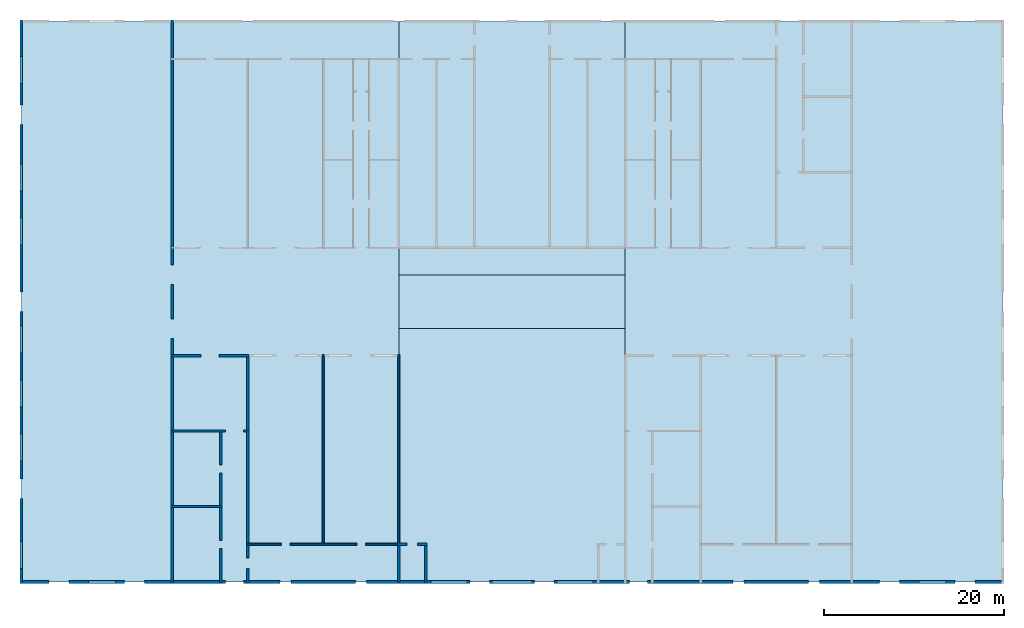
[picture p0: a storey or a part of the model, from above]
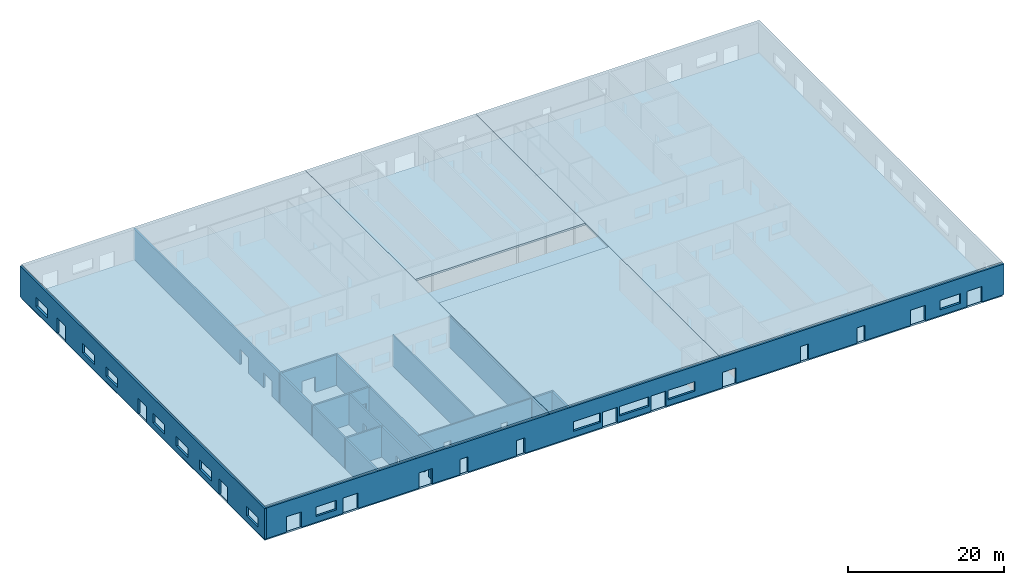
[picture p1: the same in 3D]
Properties of the parts of a building model (IFC4)

# File
Description: ViewDefinition[DesignTransferView]
File name: /dev/null
Time: 2026-10-29T19:15:48+03:00
Written by: IfcOpenShell 0.9.0.post1
Made in: IfcOpenShell 0.9.0.post1
Authorization: Nobody

# IfcBuildingStorey, Ground Floor
In: Sample Shopping Mall
Elevation: 0 mm

# IfcSpace (45)
In: Ground Floor
Name | Description | LongName = Reference
01 | الممشى الرئيسي والأتريوم | MALL STREET & ATRIUM
02 | مصاعد | LIFTS
03 | مصاعد | LIFTS
04 | المتجر الرئيسي | ANCHOR STORE W
05 | المتجر الرئيسي | ANCHOR STORE E
06 | ممر الخدمة | SERVICE CORRIDOR SW1
07 | ممر الخدمة | SERVICE CORRIDOR SE2
08 | ممر الخدمة | SERVICE CORRIDOR NW1
09 | ممر الخدمة | SERVICE CORRIDOR NE2
10 | درج الهروب | ESCAPE STAIR 1
11 | ممر الهروب | PASSAGE 1
12 | مجرى كهرباء | ELEC RISER 1
13 | مجرى ميكانيكا | MECH RISER 1
14 | محل تجاري | SHOP 01
15 | محل تجاري | SHOP 02
16 | درج الهروب | ESCAPE STAIR 2
17 | ممر الهروب | PASSAGE 2
18 | مجرى كهرباء | ELEC RISER 2
19 | مجرى ميكانيكا | MECH RISER 2
20 | محل تجاري | SHOP 03
21 | محل تجاري | SHOP 04
22 | محل تجاري | SHOP 05
23 | محل تجاري | SHOP 06
24 | ممر | LINK
25 | دورة مياه | ACCESS WC
26 | دورة مياه الرجال | MEN WC
27 | دورة مياه النساء | WOMEN WC
28 | مصلى الرجال | PRAYER M
29 | مصلى النساء | PRAYER W
30 | لوحة التوزيع | MDB
31 | مضخات الحريق | FIRE PUMP
32 | ساحة التحميل والنفايات | LOADING BAY
33 | محطة التكييف | AHU PLANT
34 | المولد | GEN SET
35 | ممر | LINK
36 | دورة مياه | ACCESS WC
37 | دورة مياه الرجال | MEN WC
38 | دورة مياه النساء | WOMEN WC
39 | مصلى الرجال | PRAYER M
40 | مصلى النساء | PRAYER W
41 | محل تجاري | SHOP 07
42 | درج الهروب | ESCAPE STAIR 3
43 | ممر الهروب | PASSAGE 3
44 | مجرى كهرباء | ELEC RISER 3
45 | مجرى ميكانيكا | MECH RISER 3

# IfcDoor (119)
In: Ground Floor
OverallHeight: 2.4 mm; PredefinedType: DOOR
Name | OverallWidth (mm)
D01 | 1.2
D02 | 1.2
D03 | 1.1
20 x  | 1.1
D04 | 1.1
D05 | 1.1
D06 | 1.1
D07 | 1.1
D08 | 1.1
D09 | 1.1
D10 | 1.1
D11 | 1.1
D12 | 1.1
D13 | 1.1
D14 | 1.1
D15 | 1.1
D16 | 1.1
D17 | 1.1
D18 | 1.1
D19 | 1.1
D20 | 1.1
D21 | 1.1
D22 | 1.1
D23 | 1.2
D24 | 1.2
D25 | 1.2
D26 | 1.2
D27 | 1.2
D28 | 1.2
D29 | 1.2
D30 | 1.2
D31 | 1
33 x  | 1
D32 | 1
D33 | 1
6 x  | 0.9
8 x  | 1.2
D37 | 1
D39 | 1
D41 | 1
D42 | 1
D43 | 1
D46 | 1
D48 | 1
D50 | 1
D52 | 1
D54 | 1.2
D62 | 1.5
2 x  | 1.5
D63 | 1.5
D68 | 1.2
D74 | 1
D76 | 1
D77 | 1
D78 | 1

# IfcSlab (5)
In: Ground Floor
Name | PredefinedType
Ground slab | FLOOR
Roof slab 0 | ROOF
Roof slab 1 | ROOF
Roof slab 2 | ROOF
Roof slab 3 | ROOF

# IfcWall: WT-150 (10)
In: Ground Floor
Type - PredefinedType: SOLIDWALL
Pset_WallCommon - IsExternal: no; LoadBearing: no
Name
W18
W19
W20
W21
W23
W24
W37
W38
W51
W52

# IfcWall: WT-200 (14)
In: Ground Floor
Type - PredefinedType: SOLIDWALL
Pset_WallCommon - IsExternal: no; LoadBearing: yes
Name
W1
W4
W10
W12
W13
W15
W25
W28
W34
W35
W36
W40
W54
W55

# IfcWall: WT-250 (32)
In: Ground Floor
Type - PredefinedType: SOLIDWALL
Pset_WallCommon - LoadBearing: yes
Name | IsExternal
W2 | no
W3 | no
W5 | no
W6 | no
W7 | no
W8 | no
W9 | no
W11 | no
W14 | no
W16 | no
W17 | no
W22 | no
W26 | no
W27 | no
W31 | yes
W32 | no
W33 | no
W39 | no
W41 | no
W42 | no
W43 | no
W44 | no
W45 | no
W46 | no
W47 | no
W48 | no
W49 | no
W50 | no
W53 | no
W56 | no
W57 | no
W58 | yes

# IfcWall: WT-300 (4)
In: Ground Floor
Type - PredefinedType: SOLIDWALL
Pset_WallCommon - IsExternal: yes; LoadBearing: yes
Name
W0
W29
W30
W59

# IfcWindow (35)
In: Ground Floor
OverallHeight: 1.5 mm; PredefinedType: WINDOW
Name | OverallWidth (mm)
2 x  | 4
 | 4.4
14 x  | 2.2
18 x  | 3
